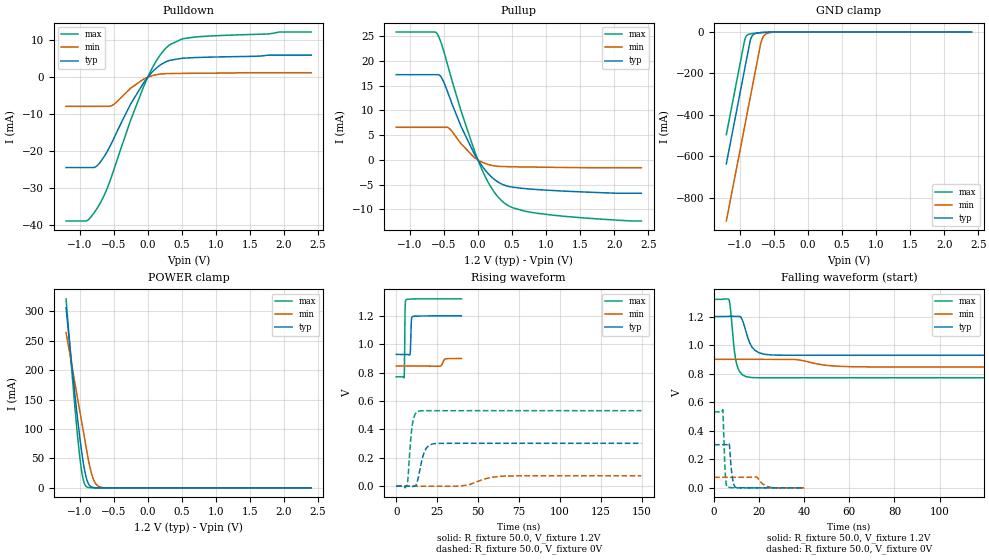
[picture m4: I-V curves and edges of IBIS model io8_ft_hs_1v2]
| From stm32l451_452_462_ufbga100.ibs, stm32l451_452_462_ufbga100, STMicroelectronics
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[Model]   io8_ft_hs_1v2
Model_type I/O
Polarity   Non-Inverting
Enable   Active-Low
| CAP_THRESHOLD on pad IOFT is "UDTCAPC" :
| Rising=30.00f vddiom   Falling=70.00f vddiom
| C_comp min and max val. don't necessarily correlate with the min and max pvt
| but are the smallest and greatest pad capacitance found.
| var   typ   min   max
C_comp   1.83456pF  1.76049pF  1.83488pF
|C_comp_pullup   1.06370pF  1.01770pF  1.04720pF
|C_comp_pulldown   770.86000fF  742.79001fF  787.68000fF
Vinl = 270.0mV
Vinh = 924.0mV
Vmeas = 600.0mV   | Reference voltage for timing measurements
Cref  = 50.0pF   | Timing specification test load capacitance value
Rref  = 100.0MOhm   | Timing specification test load resistance value
Vref  = 600.0mV   | Timing specification test load voltage
[Model Spec]
| TIME_THRESHOLD on pin ZIV12 is "CMOS" :
| Rising=50.00f vdd   Falling=50.00f vdd
Vinl 458.70000mV 364.70000mV 499.70000mV
Vinh 728.30000mV 548.30000mV 792.30000mV
| variable   typ   min   max
[Temperature Range] 25.0 140.0 -40.0
| variable   typ   min   max
[Voltage Range] 1.2V 900.0mV 1.32V
| variable   typ   min   max
[POWER Clamp Reference] 1.2V 900.0mV 1.32V
| variable   typ   min   max
[GND Clamp Reference] 0V 0V 0V
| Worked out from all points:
|   slope of the pulldown table from 0 to 0.18 V, typ, clamps not added: 55.6 ohm
|   slope of the pullup table from 0 to 0.18 V, typ, clamps not added: 56.3 ohm
|   GND clamp passes 1 mA (typ) near -0.61 V on its own axis
|   POWER clamp passes 1 mA (typ) near -0.81 V on its own axis
|   rising waveform, R_fixture 50.0, V_fixture 1.2V: 20-80 % time 429ps typ, 1.3ns min, 278ps max; typ from 0.928 V to 1.2 V
|   falling waveform, R_fixture 50.0, V_fixture 1.2V: 20-80 % time 3.78ns typ, 10.4ns min, 2.27ns max; typ from 1.2 V to 0.928 V
|   rising waveform, R_fixture 50.0, V_fixture 0V: 20-80 % time 3.76ns typ, 11.5ns min, 2.21ns max; typ from 0 V to 0.302 V
|   falling waveform, R_fixture 50.0, V_fixture 0V: 20-80 % time 1.15ns typ, 2.99ns min, 786ps max; typ from 0.302 V to 0 V
[POWER Clamp]
-1.2V     306.2mA    263.9mA    321.2mA
-1.09V    180mA      191mA      163.4mA
-1.05V    136.9mA    164.5mA    110.9mA
-1.01V    96.55mA    138mA      64.02mA
-960mV    52.29mA    104.9mA    20.68mA
-930mV    31.08mA    85.01mA    7.282mA
-900mV    15.67mA    65.13mA    2.025mA
-850mV    3.417mA    35.2mA     196.2uA
-800mV    570.2uA    14.97mA    18.13uA
-750mV    88.98uA    4.952mA    1.667uA
-680mV    6.495uA    823.9uA    58.96nA
2.4V      0A         0A         0A
[GND Clamp]
-1.2V     -636.9mA   -913.2mA   -495.8mA
-940mV    -194.9mA   -471.2mA   -53.78mA
-920mV    -160.9mA   -437.2mA   -28.06mA
-890mV    -109.9mA   -386.2mA   -14.28mA
-850mV    -43.09mA   -318.2mA   -9.18mA
-820mV    -18.33mA   -267.2mA   -7.516mA
-780mV    -7.695mA   -199.2mA   -5.87mA
-690mV    -2.548mA   -49.42mA   -2.9mA
-660mV    -1.868mA   -24.06mA   -2.112mA
-630mV    -1.326mA   -12.18mA   -1.447mA
-430mV    -19.32uA   -177.8uA   -8.091uA
2.4V      300pA      77.2nA     208.1pA
| variable   typ   min   max
[Pullup Reference] 1.2V 900.0mV 1.32V
| variable   typ   min   max
[Pulldown Reference] 0V 0V 0V
[Pullup]
-1.2V     17.25mA    6.594mA    25.88mA
-630mV    17.25mA    6.594mA    25.88mA
-600mV    17.25mA    6.594mA    25.56mA
-530mV    16.54mA    6.594mA    23.27mA
-420mV    12.82mA    6.361mA    17.99mA
-250mV    6.833mA    3.302mA    10.02mA
10mV      -217.3uA   -81.33uA   -351.4uA
200mV     -3.465mA   -1.119mA   -5.704mA
390mV     -5.137mA   -1.365mA   -8.762mA
510mV     -5.544mA   -1.401mA   -9.708mA
900mV     -6.043mA   -1.482mA   -10.87mA
2.4V      -6.768mA   -1.593mA   -12.38mA
[Pulldown]
-1.2V     -24.47mA   -7.9mA     -38.94mA
-890mV    -24.47mA   -7.9mA     -38.83mA
-720mV    -23.49mA   -7.9mA     -34.76mA
-610mV    -20.54mA   -7.9mA     -30.69mA
-510mV    -17.01mA   -7.49mA    -25.69mA
-250mV    -7.205mA   -2.955mA   -11.53mA
0V        0A         0A         -16fA
160mV     2.97mA     779.9uA    5.417mA
320mV     4.547mA    983.4uA    8.763mA
510mV     5.135mA    1.031mA    10.4mA
700mV     5.311mA    1.057mA    10.88mA
2.4V      5.965mA    1.209mA    12.22mA
[Ramp]
dV/dt_r 181.26962mV/3.75639ns 44.0861mV/11.48015ns 319.21038mV/2.19825ns
dV/dt_f 162.92582mV/3.78181ns 32.17029mV/10.39666ns 329.57189mV/2.27164ns
R_load = 50.0
| Removed startup time: 0s 0s 0s  .
| Removed end time: 39.9ns.
[Rising Waveform]
R_fixture   = 50.0
V_fixture   = 1.2V
V_fixture_min = 900.0mV
V_fixture_max = 1.32V
0s        928.4mV    846.3mV    770.7mV
4.8ns     928.5mV    846.4mV    764.7mV
5.1ns     928.5mV    846.4mV    885.1mV
5.4ns     928.5mV    846.4mV    1.238V
6ns       928.5mV    846.4mV    1.314V
8.4ns     927mV      846.4mV    1.319V
8.7ns     966.5mV    846.4mV    1.319V
9.3ns     1.17V      846.4mV    1.319V
10ns      1.196V     846.4mV    1.32V
39.9ns    1.2V       899.7mV    1.32V
| Removed startup time: 0s 0s 0s  .
| Removed end time: 149.9ns.
[Falling Waveform]
R_fixture   = 50.0
V_fixture   = 1.2V
V_fixture_min = 900.0mV
V_fixture_max = 1.32V
0s        1.2V       900mV      1.32V
6.7ns     1.201V     900mV      1.316V
8.9ns     1.202V     900mV      972.3mV
9.9ns     1.202V     900mV      874.1mV
11.9ns    1.196V     900mV      802.7mV
14.2ns    1.091V     900mV      778.6mV
18ns      964.8mV    899.9mV    771.7mV
25.5ns    930.4mV    900.4mV    770.7mV
59.8ns    928.5mV    848.8mV    770.7mV
149.9ns   928.5mV    846.4mV    770.7mV
| Removed startup time: 0s 0s 0s  .
| Removed end time: 149.9ns.
[Rising Waveform]
R_fixture   = 50.0
V_fixture   = 0V
V_fixture_min = 0V
V_fixture_max = 0V
0s        -21.52uV   -19.2uV    -16.69uV
6.6ns     92.12nV    212.2nV    3.073mV
7.2ns     29.66uV    184.2nV    52.81mV
9.7ns     -4.874mV   167.6nV    423.4mV
12.1ns    5.843mV    200.8nV    515.7mV
13.9ns    83.49mV    113.1nV    529.1mV
16.9ns    232.8mV    -27.83nV   531.8mV
22ns      297.2mV    2.952uV    532mV
64.7ns    302.1mV    70.19mV    532mV
149.9ns   302.1mV    73.48mV    532mV
| Removed startup time: 0s 0s 0s  .
| Removed end time: 39.9ns.
[Falling Waveform]
R_fixture   = 50.0
V_fixture   = 0V
V_fixture_min = 0V
V_fixture_max = 0V
0s        302.1mV    73.47mV    532mV
3.9ns     302.1mV    73.46mV    542.4mV
4.8ns     302mV      73.46mV    149.8mV
5.3ns     301.8mV    73.46mV    34.07mV
5.7ns     301.4mV    73.46mV    5.584mV
6.7ns     311.1mV    73.46mV    2.56mV
7.8ns     107.8mV    73.46mV    976.5uV
9.2ns     5.754mV    73.46mV    394.7uV
26ns      4.46uV     1.169mV    -6.739uV
39.9ns    -2.54uV    150.5uV    -6.345uV
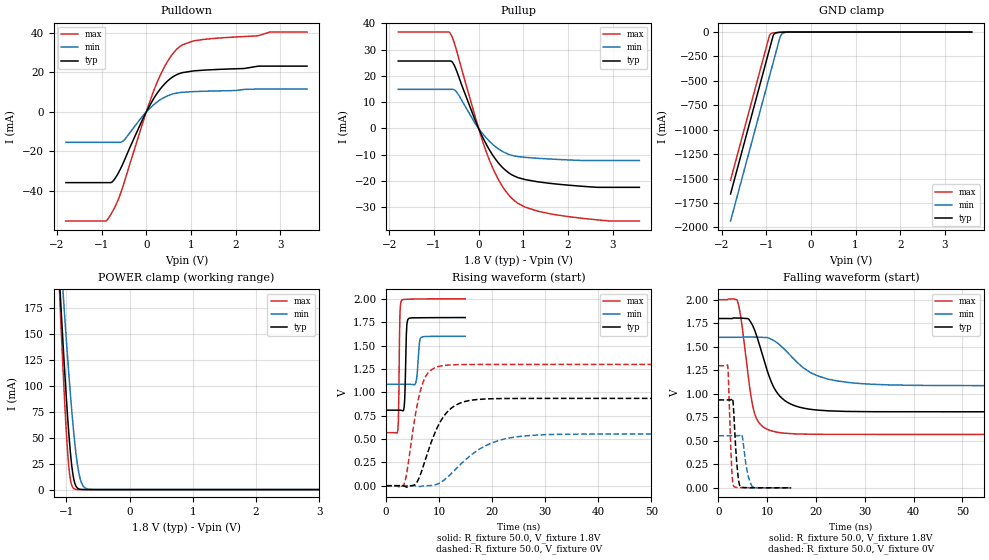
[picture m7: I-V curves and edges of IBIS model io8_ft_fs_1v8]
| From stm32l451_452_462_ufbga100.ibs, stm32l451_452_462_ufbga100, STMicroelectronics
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[Model]   io8_ft_fs_1v8
Model_type I/O
Polarity   Non-Inverting
Enable   Active-Low
| CAP_THRESHOLD on pad IOFT is "UDTCAPC" :
| Rising=30.00f vddiom   Falling=70.00f vddiom
| C_comp min and max val. don't necessarily correlate with the min and max pvt
| but are the smallest and greatest pad capacitance found.
| var   typ   min   max
C_comp   2.04484pF  2.03950pF  2.10330pF
|C_comp_pullup   1.14452pF  1.14098pF  1.14605pF
|C_comp_pulldown   900.31992fF  898.52017fF  957.25003fF
Vinl = 480.0mV
Vinh = 1.4V
Vmeas = 900.0mV   | Reference voltage for timing measurements
Cref  = 50.0pF   | Timing specification test load capacitance value
Rref  = 100.0MOhm   | Timing specification test load resistance value
Vref  = 900.0mV   | Timing specification test load voltage
[Model Spec]
| TIME_THRESHOLD on pin ZIV12 is "CMOS" :
| Rising=50.00f vdd   Falling=50.00f vdd
Vinl 728.70000mV 655.70000mV 817.70000mV
Vinh 1.06430V 949.30000mV 1.16330V
| variable   typ   min   max
[Temperature Range] 25.0 140.0 -40.0
| variable   typ   min   max
[Voltage Range] 1.8V 1.6V 2.0V
| variable   typ   min   max
[POWER Clamp Reference] 1.8V 1.6V 2.0V
| variable   typ   min   max
[GND Clamp Reference] 0V 0V 0V
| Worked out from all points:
|   slope of the pulldown table from 0 to 0.27 V, typ, clamps not added: 26.3 ohm
|   slope of the pullup table from 0 to 0.27 V, typ, clamps not added: 30 ohm
|   GND clamp passes 1 mA (typ) near -0.61 V on its own axis
|   POWER clamp passes 1 mA (typ) near -0.81 V on its own axis
|   rising waveform, R_fixture 50.0, V_fixture 1.8V: 20-80 % time 252ps typ, 394ps min, 202ps max; typ from 0.809 V to 1.8 V
|   falling waveform, R_fixture 50.0, V_fixture 1.8V: 20-80 % time 4.16ns typ, 7.38ns min, 2.24ns max; typ from 1.8 V to 0.809 V
|   rising waveform, R_fixture 50.0, V_fixture 0V: 20-80 % time 4.05ns typ, 7.36ns min, 2.34ns max; typ from 0 V to 0.935 V
|   falling waveform, R_fixture 50.0, V_fixture 0V: 20-80 % time 697ps typ, 1.02ns min, 535ps max; typ from 0.935 V to 0 V
[POWER Clamp]
-1.8V     1.053A     943.1mA    1.262A
-1.11V    202.2mA    242.3mA    190.9mA
-1.09V    180mA      223.6mA    163.4mA
-1.05V    136.9mA    187mA      110.9mA
-980mV    68.91mA    126.1mA    35.23mA
-940mV    37.57mA    94.11mA    10.65mA
-880mV    8.969mA    52.17mA    807.4uA
-830mV    1.697mA    25.82mA    75.79uA
-790mV    394.2uA    12.22mA    11.25uA
-740mV    61.25uA    3.879mA    1.034uA
-660mV    3.073uA    483.4uA    22.7nA
3.6V      0A         0A         0A
[GND Clamp]
-1.8V     -1.658A    -1.935A    -1.517A
-930mV    -179mA     -456mA     -38.91mA
-900mV    -128mA     -405mA     -17.65mA
-850mV    -44.09mA   -320mA     -9.519mA
-830mV    -24.74mA   -286mA     -8.302mA
-790mV    -9.695mA   -218mA     -6.49mA
-700mV    -2.938mA   -65mA      -3.294mA
-670mV    -2.157mA   -31.85mA   -2.435mA
-640mV    -1.545mA   -16.21mA   -1.699mA
-570mV    -571.9uA   -3.807mA   -536.5uA
-420mV    -14.26uA   -143.3uA   -5.434uA
3.6V      450.9pA    102.5nA    318pA
| variable   typ   min   max
[Pullup Reference] 1.8V 1.6V 2.0V
| variable   typ   min   max
[Pulldown Reference] 0V 0V 0V
[Pullup]
-1.8V     25.66mA    14.85mA    36.7mA
-630mV    25.66mA    14.85mA    36.09mA
-570mV    24.8mA     14.85mA    33.82mA
-480mV    21.34mA    13.54mA    28.84mA
-90mV     3.62mA     2.224mA    5.223mA
230mV     -7.853mA   -4.702mA   -11.57mA
540mV     -15mA      -8.867mA   -22.31mA
870mV     -18.72mA   -10.75mA   -28.48mA
1.33V     -20.4mA    -11.44mA   -31.6mA
1.9V      -21.5mA    -11.96mA   -33.39mA
2.94V     -22.49mA   -12.26mA   -35.33mA
3.6V      -22.49mA   -12.26mA   -35.33mA
[Pulldown]
-1.8V     -35.76mA   -15.41mA   -55.17mA
-910mV    -35.76mA   -15.41mA   -55.17mA
-830mV    -35.76mA   -15.41mA   -53.18mA
-710mV    -34mA      -15.41mA   -48.42mA
-520mV    -26.05mA   -14.75mA   -37.5mA
-90mV     -4.145mA   -2.306mA   -6.327mA
230mV     8.974mA    4.797mA    14.24mA
490mV     15.87mA    8.223mA    26.01mA
750mV     19.43mA    9.743mA    33.01mA
1.33V     21.16mA    10.45mA    36.75mA
2.78V     23.13mA    11.52mA    40.36mA
3.6V      23.13mA    11.52mA    40.37mA
[Ramp]
dV/dt_r 560.73224mV/4.0466ns 332.41097mV/7.35894ns 778.78366mV/2.34456ns
dV/dt_f 594.84215mV/4.15576ns 308.28551mV/7.3798ns 859.12507mV/2.24125ns
R_load = 50.0
| Removed startup time: 0s 0s 0s  .
| Removed end time: 14.9ns.
[Rising Waveform]
R_fixture   = 50.0
V_fixture   = 1.8V
V_fixture_min = 1.6V
V_fixture_max = 2.0V
0s        808.6mV    1.086V     568.1mV
2.2ns     808.7mV    1.086V     590.5mV
2.6ns     808.5mV    1.086V     1.843V
2.9ns     806.4mV    1.086V     1.983V
3.4ns     844.7mV    1.086V     1.994V
3.8ns     1.615V     1.086V     1.995V
4.1ns     1.779V     1.086V     1.996V
5.6ns     1.797V     1.105V     1.998V
6.6ns     1.798V     1.587V     1.999V
14.9ns    1.8V       1.599V     2V
| Removed startup time: 0s 0s 0s  .
| Removed end time: 99.9ns.
[Falling Waveform]
R_fixture   = 50.0
V_fixture   = 1.8V
V_fixture_min = 1.6V
V_fixture_max = 2.0V
0s        1.8V       1.6V       2V
3.9ns     1.804V     1.6V       1.985V
4.7ns     1.805V     1.6V       1.77V
6.1ns     1.797V     1.603V     1.186V
7.3ns     1.691V     1.603V     809.7mV
10.8ns    1.13V      1.58V      606.1mV
15.5ns    875.6mV    1.366V     573.8mV
20.6ns    825.2mV    1.185V     568.8mV
27.4ns    811.5mV    1.116V     568.1mV
99.9ns    808.6mV    1.086V     568.1mV
| Removed startup time: 0s 0s 0s  .
| Removed end time: 99.9ns.
[Rising Waveform]
R_fixture   = 50.0
V_fixture   = 0V
V_fixture_min = 0V
V_fixture_max = 0V
0s        -16.13uV   -14.82uV   -10.77uV
3.3ns     -2.301mV   55.51nV    9.608mV
3.9ns     -16.13mV   1.249uV    142.3mV
5.5ns     16.28mV    -1.813mV   755.5mV
6.7ns     158.2mV    -4.761mV   1.064V
10.1ns    674.3mV    29.18mV    1.279V
14.7ns    899.3mV    264.6mV    1.297V
19.5ns    930.4mV    449.3mV    1.298V
25.7ns    934.3mV    530.8mV    1.298V
99.9ns    934.6mV    554mV      1.298V
| Removed startup time: 0s 0s 0s  .
| Removed end time: 14.9ns.
[Falling Waveform]
R_fixture   = 50.0
V_fixture   = 0V
V_fixture_min = 0V
V_fixture_max = 0V
0s        934.6mV    554mV      1.298V
1.9ns     934.6mV    554mV      1.301V
2.7ns     941.3mV    554mV      214.2mV
3.1ns     830.2mV    554mV      18.98mV
3.8ns     232.2mV    553.6mV    3.691mV
4.5ns     10.18mV    562.3mV    2.755mV
4.9ns     3.746mV    542.5mV    1.941mV
6ns       1.827mV    145.7mV    801.4uV
6.9ns     1.538mV    15.55mV    524.7uV
14.9ns    124.7uV    373.7uV    20.31uV
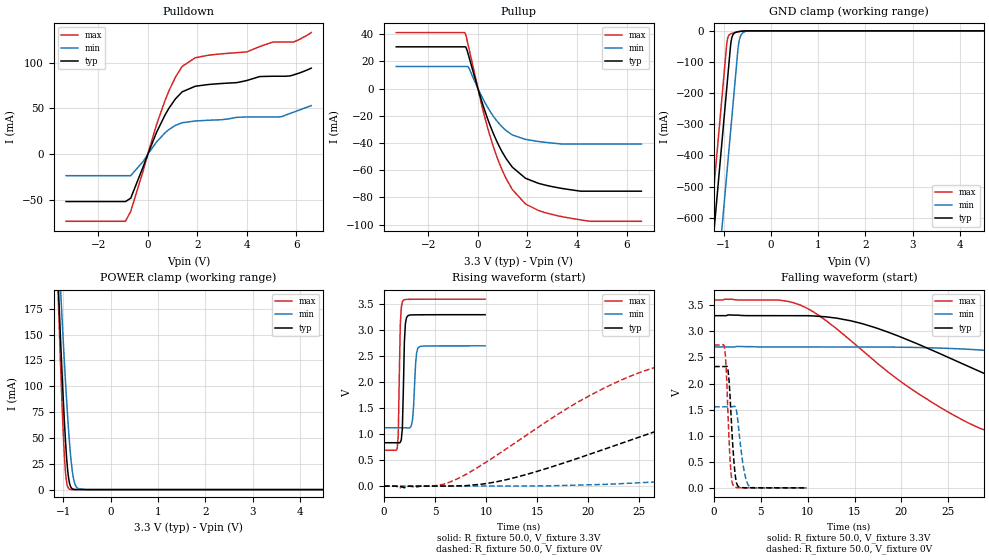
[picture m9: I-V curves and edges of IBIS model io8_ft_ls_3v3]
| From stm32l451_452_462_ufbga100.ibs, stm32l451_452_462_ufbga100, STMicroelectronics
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[Model]   io8_ft_ls_3v3
Model_type I/O
Polarity   Non-Inverting
Enable   Active-Low
| CAP_THRESHOLD on pad IOFT is "UDTCAPC" :
| Rising=30.00f vddiom   Falling=70.00f vddiom
| C_comp min and max val. don't necessarily correlate with the min and max pvt
| but are the smallest and greatest pad capacitance found.
| var   typ   min   max
C_comp   2.21482pF  2.18664pF  2.96107pF
|C_comp_pullup   1.17150pF  1.24168pF  1.62372pF
|C_comp_pulldown   1.04333pF  944.96079fF  1.33735pF
Vinl = 810.0mV
Vinh = 2.52V
Vmeas = 1.65V   | Reference voltage for timing measurements
Cref  = 50.0pF   | Timing specification test load capacitance value
Rref  = 100.0MOhm   | Timing specification test load resistance value
Vref  = 1.65V   | Timing specification test load voltage
[Model Spec]
| TIME_THRESHOLD on pin ZIV12 is "CMOS" :
| Rising=50.00f vdd   Falling=50.00f vdd
Vinl 1.34770V 1.11470V 1.44970V
Vinh 1.77530V 1.49030V 1.90330V
| variable   typ   min   max
[Temperature Range] 25.0 140.0 -40.0
| variable   typ   min   max
[Voltage Range] 3.3V 2.7V 3.6V
| variable   typ   min   max
[POWER Clamp Reference] 3.3V 2.7V 3.6V
| variable   typ   min   max
[GND Clamp Reference] 0V 0V 0V
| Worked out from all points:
|   slope of the pulldown table from 0 to 0.495 V, typ, clamps not added: 15.6 ohm
|   slope of the pullup table from 0 to 0.495 V, typ, clamps not added: 18.1 ohm
|   GND clamp passes 1 mA (typ) near -0.60 V on its own axis
|   POWER clamp passes 1 mA (typ) near -0.81 V on its own axis
|   rising waveform, R_fixture 50.0, V_fixture 3.3V: 20-80 % time 179ps typ, 248ps min, 164ps max; typ from 0.835 V to 3.3 V
|   falling waveform, R_fixture 50.0, V_fixture 3.3V: 20-80 % time 21.1ns typ, 46.4ns min, 13.6ns max; typ from 3.3 V to 0.835 V
|   rising waveform, R_fixture 50.0, V_fixture 0V: 20-80 % time 24.2ns typ, 57.6ns min, 14.4ns max; typ from 0 V to 2.33 V
|   falling waveform, R_fixture 50.0, V_fixture 0V: 20-80 % time 471ps typ, 665ps min, 386ps max; typ from 2.33 V to 0 V
[POWER Clamp]
-3.3V     2.991A     2.546A     3.694A
-1.11V    202.2mA    242.3mA    190.9mA
-1.09V    180mA      223.6mA    163.4mA
-1.05V    136.9mA    187mA      110.9mA
-1.01V    96.55mA    151.6mA    64.02mA
-970mV    60.39mA    117.9mA    27.41mA
-930mV    31.08mA    86.54mA    7.282mA
-860mV    4.779mA    40.5mA     315.2uA
-810mV    823.2uA    18.15mA    29.21uA
-750mV    88.98uA    4.952mA    1.667uA
-510mV    11.25nA    8.405uA    51.8pA
6.6V      0A         0A         0A
[GND Clamp]
-3.3V     -4.209A    -4.487A    -4.067A
-1.41V    -996.3mA   -1.274A    -854.3mA
-1.25V    -724.3mA   -1.002A    -582.3mA
-1.21V    -656.3mA   -933.6mA   -514.3mA
-930mV    -180.3mA   -457.6mA   -39.53mA
-900mV    -129.3mA   -406.6mA   -18.05mA
-840mV    -33.79mA   -304.6mA   -9.105mA
-790mV    -10.15mA   -219.6mA   -6.665mA
-680mV    -2.476mA   -41.57mA   -2.768mA
-630mV    -1.406mA   -13.77mA   -1.51mA
-530mV    -268.4uA   -1.762mA   -214.9uA
6.6V      833.9pA    196.4nA    597.5pA
| variable   typ   min   max
[Pullup Reference] 3.3V 2.7V 3.6V
| variable   typ   min   max
[Pulldown Reference] 0V 0V 0V
[Pullup]
-3.3V     30.64mA    16.16mA    41.13mA
-530mV    30.64mA    16.16mA    41.01mA
-470mV    29.67mA    16.16mA    37.87mA
-370mV    23.8mA     15.16mA    30.04mA
250mV     -14.78mA   -9.185mA   -19.21mA
730mV     -37.54mA   -23mA      -48.39mA
990mV     -46.97mA   -28.45mA   -60.4mA
1.39V     -57.81mA   -34.14mA   -74.25mA
1.92V     -65.96mA   -37.4mA    -84.89mA
2.7V      -70.92mA   -39.51mA   -91.15mA
4.35V     -75.45mA   -40.79mA   -97.1mA
6.6V      -75.45mA   -40.79mA   -97.6mA
[Pulldown]
-3.3V     -51.64mA   -23.39mA   -73.18mA
-900mV    -51.64mA   -23.39mA   -73.04mA
-690mV    -47.97mA   -23.39mA   -62.4mA
350mV     23.63mA    13.27mA    31.99mA
690mV     42.49mA    23.17mA    58.21mA
1.12V     60.48mA    31.51mA    84.25mA
1.39V     68.1mA     34.34mA    95.86mA
1.92V     74.17mA    36.28mA    105.3mA
4V        80.41mA    40.64mA    111.6mA
5.39V     85.07mA    40.9mA     122.4mA
5.88V     86.5mA     45.8mA     122.4mA
6.6V      93.9mA     53mA       132.7mA
[Ramp]
dV/dt_r 1.39485V/24.15437ns 931.92574mV/56.84897ns 1.64323V/14.42144ns
dV/dt_f 1.47909V/21.045ns 946.45573mV/46.41739ns 1.74613V/13.56273ns
R_load = 50.0
| Removed startup time: 0s 0s 0s  .
| Removed end time: 9.9ns.
[Rising Waveform]
R_fixture   = 50.0
V_fixture   = 3.3V
V_fixture_min = 2.7V
V_fixture_max = 3.6V
0s        834.8mV    1.123V     689.8mV
1.3ns     834.4mV    1.123V     730mV
1.4ns     833.9mV    1.123V     967.8mV
1.6ns     841.3mV    1.123V     3.106V
1.9ns     1.854V     1.122V     3.577V
2ns       2.775V     1.122V     3.588V
2.3ns     3.271V     1.12V      3.595V
2.8ns     3.296V     1.282V     3.596V
3.4ns     3.297V     2.673V     3.597V
9.9ns     3.299V     2.7V       3.599V
| Removed startup time: 0s 0s 0s  .
| Removed end time: 499.9ns.
[Falling Waveform]
R_fixture   = 50.0
V_fixture   = 3.3V
V_fixture_min = 2.7V
V_fixture_max = 3.6V
0s        3.3V       2.7V       3.6V
9.8ns     3.3V       2.7V       3.454V
17.1ns    3.077V     2.7V       2.438V
23.6ns    2.613V     2.682V     1.602V
29.9ns    2.111V     2.626V     1.041V
39.7ns    1.454V     2.465V     814.1mV
47ns      1.151V     2.311V     762.5mV
84.3ns    884.4mV    1.511V     699.4mV
131.6ns   843.7mV    1.221V     690.8mV
499.9ns   834.9mV    1.123V     689.8mV
| Removed startup time: 0s 0s 0s  .
| Removed end time: 499.9ns.
[Rising Waveform]
R_fixture   = 50.0
V_fixture   = 0V
V_fixture_min = 0V
V_fixture_max = 0V
0s        -11.67uV   -15.22uV   -4.062uV
6.9ns     2.994mV    -132.1uV   113.3mV
11.9ns    119.5mV    268.2uV    706.7mV
19.3ns    556.4mV    19.79mV    1.652V
26.5ns    1.046V     78.86mV    2.284V
44.6ns    1.943V     376.1mV    2.663V
58.7ns    2.179V     654.6mV    2.712V
90.5ns    2.296V     1.16V      2.736V
131.6ns   2.321V     1.445V     2.739V
499.9ns   2.325V     1.553V     2.739V
| Removed startup time: 0s 0s 0s  .
| Removed end time: 9.9ns.
[Falling Waveform]
R_fixture   = 50.0
V_fixture   = 0V
V_fixture_min = 0V
V_fixture_max = 0V
0s        2.325V     1.553V     2.739V
1.1ns     2.324V     1.553V     2.713V
1.3ns     2.331V     1.553V     2.274V
1.5ns     2.242V     1.553V     1.348V
1.8ns     1.433V     1.553V     292.3mV
2.1ns     549.2mV    1.562V     31.3mV
2.5ns     45.86mV    1.345V     4.942mV
3.1ns     3.341mV    440.6mV    2.503mV
3.7ns     1.894mV    39.84mV    1.906mV
9.9ns     418.9uV    295.7uV    563.6uV
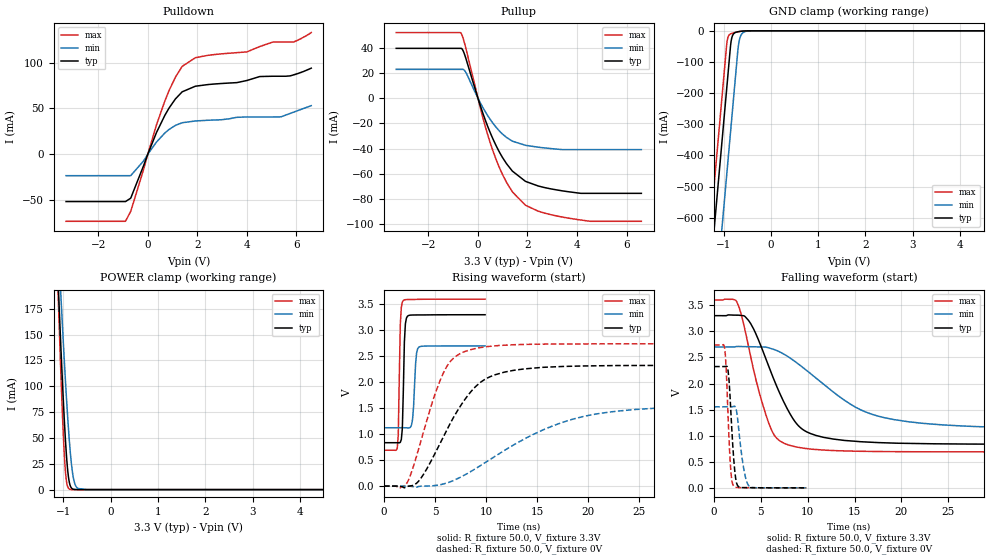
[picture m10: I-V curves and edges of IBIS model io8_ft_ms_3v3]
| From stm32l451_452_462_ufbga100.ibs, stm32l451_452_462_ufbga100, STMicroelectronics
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[Model]   io8_ft_ms_3v3
Model_type I/O
Polarity   Non-Inverting
Enable   Active-Low
| CAP_THRESHOLD on pad IOFT is "UDTCAPC" :
| Rising=30.00f vddiom   Falling=70.00f vddiom
| C_comp min and max val. don't necessarily correlate with the min and max pvt
| but are the smallest and greatest pad capacitance found.
| var   typ   min   max
C_comp   2.21481pF  2.18664pF  2.96106pF
|C_comp_pullup   1.17150pF  1.24174pF  1.62375pF
|C_comp_pulldown   1.04331pF  944.90079fF  1.33731pF
Vinl = 810.0mV
Vinh = 2.52V
Vmeas = 1.65V   | Reference voltage for timing measurements
Cref  = 50.0pF   | Timing specification test load capacitance value
Rref  = 100.0MOhm   | Timing specification test load resistance value
Vref  = 1.65V   | Timing specification test load voltage
[Model Spec]
| TIME_THRESHOLD on pin ZIV12 is "CMOS" :
| Rising=50.00f vdd   Falling=50.00f vdd
Vinl 1.34770V 1.11470V 1.44970V
Vinh 1.77530V 1.49030V 1.90330V
| variable   typ   min   max
[Temperature Range] 25.0 140.0 -40.0
| variable   typ   min   max
[Voltage Range] 3.3V 2.7V 3.6V
| variable   typ   min   max
[POWER Clamp Reference] 3.3V 2.7V 3.6V
| variable   typ   min   max
[GND Clamp Reference] 0V 0V 0V
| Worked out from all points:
|   slope of the pulldown table from 0 to 0.495 V, typ, clamps not added: 15.6 ohm
|   slope of the pullup table from 0 to 0.495 V, typ, clamps not added: 18.1 ohm
|   GND clamp passes 1 mA (typ) near -0.60 V on its own axis
|   POWER clamp passes 1 mA (typ) near -0.81 V on its own axis
|   rising waveform, R_fixture 50.0, V_fixture 3.3V: 20-80 % time 179ps typ, 248ps min, 164ps max; typ from 0.835 V to 3.3 V
|   falling waveform, R_fixture 50.0, V_fixture 3.3V: 20-80 % time 3.61ns typ, 7.5ns min, 2.46ns max; typ from 3.3 V to 0.835 V
|   rising waveform, R_fixture 50.0, V_fixture 0V: 20-80 % time 4.13ns typ, 8.96ns min, 2.71ns max; typ from 0 V to 2.33 V
|   falling waveform, R_fixture 50.0, V_fixture 0V: 20-80 % time 471ps typ, 665ps min, 387ps max; typ from 2.33 V to 0 V
[POWER Clamp]
-3.3V     2.991A     2.546A     3.694A
-1.11V    202.2mA    242.3mA    190.9mA
-1.09V    180mA      223.6mA    163.4mA
-1.05V    136.9mA    187mA      110.9mA
-1.01V    96.55mA    151.6mA    64.02mA
-970mV    60.39mA    117.9mA    27.41mA
-930mV    31.08mA    86.54mA    7.282mA
-860mV    4.779mA    40.5mA     315.2uA
-810mV    823.2uA    18.15mA    29.21uA
-750mV    88.98uA    4.952mA    1.667uA
-510mV    11.25nA    8.405uA    51.8pA
6.6V      0A         0A         0A
[GND Clamp]
-3.3V     -4.209A    -4.487A    -4.067A
-1.41V    -996.3mA   -1.274A    -854.3mA
-1.25V    -724.3mA   -1.002A    -582.3mA
-1.21V    -656.3mA   -933.6mA   -514.3mA
-930mV    -180.3mA   -457.6mA   -39.53mA
-900mV    -129.3mA   -406.6mA   -18.05mA
-840mV    -33.79mA   -304.6mA   -9.105mA
-790mV    -10.15mA   -219.6mA   -6.665mA
-680mV    -2.476mA   -41.57mA   -2.768mA
-630mV    -1.406mA   -13.77mA   -1.51mA
-530mV    -268.4uA   -1.762mA   -214.9uA
6.6V      833.9pA    196.4nA    597.5pA
| variable   typ   min   max
[Pullup Reference] 3.3V 2.7V 3.6V
| variable   typ   min   max
[Pulldown Reference] 0V 0V 0V
[Pullup]
-3.3V     39.39mA    22.76mA    51.9mA
-690mV    39.39mA    22.76mA    51.61mA
-600mV    37.53mA    22.73mA    47.48mA
-480mV    31mA       20.05mA    38.86mA
270mV     -15.88mA   -9.861mA   -20.62mA
730mV     -37.54mA   -23mA      -48.39mA
990mV     -46.97mA   -28.45mA   -60.4mA
1.39V     -57.81mA   -34.14mA   -74.25mA
1.92V     -65.96mA   -37.41mA   -84.89mA
2.7V      -70.92mA   -39.51mA   -91.15mA
4.35V     -75.45mA   -40.79mA   -97.1mA
6.6V      -75.45mA   -40.79mA   -97.6mA
[Pulldown]
-3.3V     -51.64mA   -23.39mA   -73.18mA
-900mV    -51.64mA   -23.39mA   -73.04mA
-690mV    -47.97mA   -23.39mA   -62.4mA
350mV     23.63mA    13.27mA    31.99mA
690mV     42.49mA    23.17mA    58.21mA
1.12V     60.48mA    31.51mA    84.25mA
1.39V     68.1mA     34.34mA    95.86mA
1.92V     74.17mA    36.28mA    105.3mA
4V        80.41mA    40.64mA    111.6mA
5.39V     85.07mA    40.9mA     122.4mA
5.88V     86.5mA     45.8mA     122.4mA
6.6V      93.9mA     53mA       132.7mA
[Ramp]
dV/dt_r 1.39485V/4.13204ns 931.93233mV/8.96078ns 1.64323V/2.70748ns
dV/dt_f 1.47909V/3.60928ns 946.45837mV/7.49824ns 1.74611V/2.4636ns
R_load = 50.0
| Removed startup time: 0s 0s 0s  .
| Removed end time: 9.9ns.
[Rising Waveform]
R_fixture   = 50.0
V_fixture   = 3.3V
V_fixture_min = 2.7V
V_fixture_max = 3.6V
0s        834.8mV    1.123V     689.8mV
1.3ns     834.4mV    1.123V     729.9mV
1.4ns     833.9mV    1.123V     970.3mV
1.6ns     840.9mV    1.123V     3.105V
1.9ns     1.857V     1.122V     3.574V
2ns       2.775V     1.122V     3.585V
2.3ns     3.27V      1.12V      3.591V
2.8ns     3.294V     1.284V     3.592V
3.4ns     3.295V     2.672V     3.596V
9.9ns     3.299V     2.699V     3.6V
| Removed startup time: 0s 0s 0s  .
| Removed end time: 99.9ns.
[Falling Waveform]
R_fixture   = 50.0
V_fixture   = 3.3V
V_fixture_min = 2.7V
V_fixture_max = 3.6V
0s        3.3V       2.7V       3.6V
2.4ns     3.311V     2.71V      3.572V
3.7ns     3.204V     2.707V     2.694V
4.9ns     2.767V     2.7V       1.779V
6.3ns     2.116V     2.658V     1.049V
8.1ns     1.422V     2.49V      813.4mV
9.4ns     1.128V     2.319V     763.2mV
16.1ns    880.2mV    1.461V     699.6mV
23.6ns    844.4mV    1.217V     691.2mV
99.9ns    834.9mV    1.123V     689.8mV
| Removed startup time: 0s 0s 0s  .
| Removed end time: 99.9ns.
[Rising Waveform]
R_fixture   = 50.0
V_fixture   = 0V
V_fixture_min = 0V
V_fixture_max = 0V
0s        -11.67uV   -15.21uV   -4.076uV
2.3ns     -6.503mV   326uV      75.33mV
3.7ns     173.2mV    -2.076mV   922.7mV
5.2ns     706.6mV    15.02mV    1.881V
6.4ns     1.175V     75.25mV    2.376V
8.3ns     1.766V     256.2mV    2.616V
10ns      2.067V     461.8mV    2.683V
17.6ns    2.303V     1.234V     2.737V
25.8ns    2.323V     1.49V      2.739V
99.9ns    2.325V     1.553V     2.739V
| Removed startup time: 0s 0s 0s  .
| Removed end time: 9.9ns.
[Falling Waveform]
R_fixture   = 50.0
V_fixture   = 0V
V_fixture_min = 0V
V_fixture_max = 0V
0s        2.325V     1.553V     2.739V
1.1ns     2.324V     1.553V     2.713V
1.3ns     2.331V     1.553V     2.273V
1.5ns     2.241V     1.553V     1.347V
1.8ns     1.432V     1.553V     293.1mV
2.1ns     548.7mV    1.561V     33.46mV
2.5ns     47.16mV    1.344V     7.242mV
3.1ns     4.873mV    440mV      4.968mV
3.7ns     3.572mV    40.28mV    2.637mV
9.9ns     370.5uV    700.6uV    251.5uV
